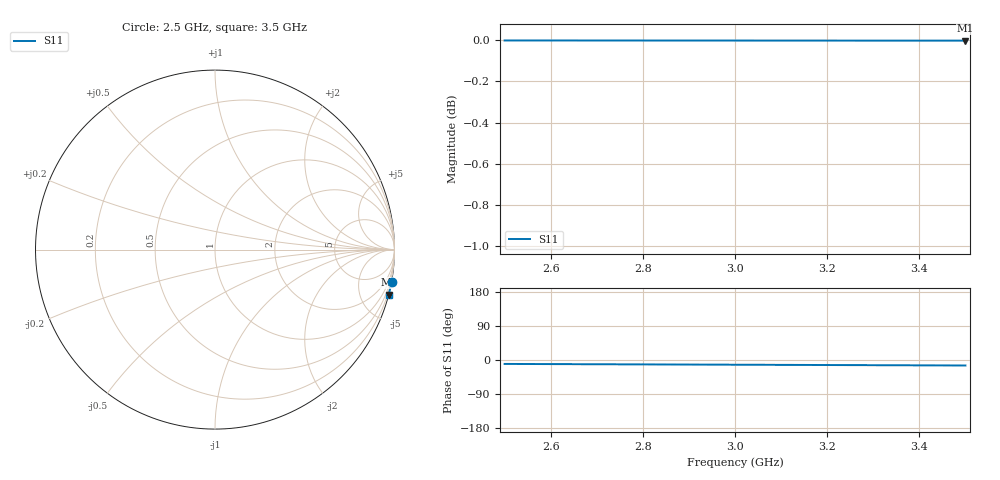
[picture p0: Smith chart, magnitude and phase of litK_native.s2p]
! Sonnet Data File
! From: em Version : 18.53-Lite
! From Project: litK
! Data is NOT De-embedded
! Data File Written: 10/12/2026 16:51:09
!< HDATE 10/24/2012 09:32:25
!< MDATE 10/24/2012 09:32:25
# GHZ S RI R 50.00000
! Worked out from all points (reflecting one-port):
!   201 points, 2.5 GHz to 3.5 GHz, reference 50 ohm
!   lowest |S11| = 0.0 dB at 3.5 GHz (marker M1)
!   phase of S11 starts at -10 deg and turns -4 deg over the sweep
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2.5  0.9835 -0.18
2.53  0.9831 -0.1821
2.56  0.9828 -0.1842
2.59  0.9823 -0.1864
2.625  0.9819 -0.1888
2.655  0.9815 -0.191
2.685  0.981 -0.1931
2.715  0.9806 -0.1952
2.75  0.9801 -0.1977
2.81  0.9793 -0.2019
2.84  0.9788 -0.204
2.875  0.9783 -0.2065
2.935  0.9774 -0.2107
2.965  0.9769 -0.2128
3  0.9764 -0.2153
3.06  0.9754 -0.2195
3.095  0.9749 -0.222
3.125  0.9744 -0.2241
3.16  0.9738 -0.2265
3.19  0.9733 -0.2286
3.22  0.9728 -0.2307
3.25  0.9723 -0.2328
3.28  0.9718 -0.2349
3.315  0.9712 -0.2374
3.345  0.9707 -0.2395
3.375  0.9702 -0.2416
3.44  0.969 -0.2461
3.5  0.9679 -0.2502
